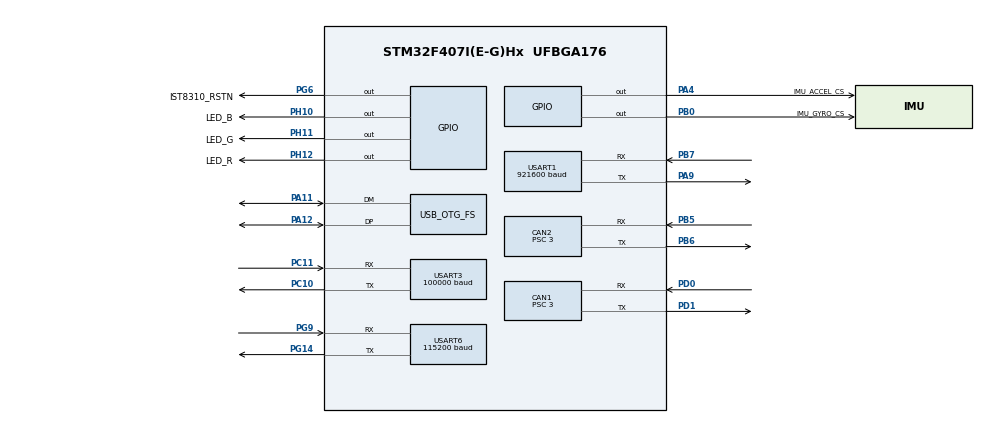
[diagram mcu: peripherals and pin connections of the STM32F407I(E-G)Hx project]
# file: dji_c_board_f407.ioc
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CAN1.BS1=CAN_BS1_10TQ
CAN1.BS2=CAN_BS2_3TQ
CAN1.CalculateBaudRate=1000000
CAN1.CalculateTimeBit=1000
CAN1.CalculateTimeQuantum=71.42857142857143
CAN1.Prescaler=3
CAN2.BS1=CAN_BS1_10TQ
CAN2.BS2=CAN_BS2_3TQ
CAN2.CalculateBaudRate=1000000
CAN2.CalculateTimeBit=1000
CAN2.CalculateTimeQuantum=71.42857142857143
CAN2.Prescaler=3
Dma.Request0=USART1_RX
Dma.Request1=USART1_TX
Dma.Request2=USART3_RX
Dma.Request3=USART6_RX
Dma.Request4=USART6_TX
Dma.USART1_RX.0.Direction=DMA_PERIPH_TO_MEMORY
Dma.USART1_RX.0.FIFOMode=DMA_FIFOMODE_DISABLE
Dma.USART1_RX.0.Instance=DMA2_Stream2
Dma.USART1_RX.0.MemDataAlignment=DMA_MDATAALIGN_BYTE
Dma.USART1_RX.0.MemInc=DMA_MINC_ENABLE
Dma.USART1_RX.0.Mode=DMA_NORMAL
Dma.USART1_RX.0.PeriphDataAlignment=DMA_PDATAALIGN_BYTE
Dma.USART1_RX.0.PeriphInc=DMA_PINC_DISABLE
Dma.USART1_RX.0.Priority=DMA_PRIORITY_LOW
Dma.USART1_TX.1.Direction=DMA_MEMORY_TO_PERIPH
Dma.USART1_TX.1.FIFOMode=DMA_FIFOMODE_DISABLE
Dma.USART1_TX.1.Instance=DMA2_Stream7
Dma.USART1_TX.1.MemDataAlignment=DMA_MDATAALIGN_BYTE
Dma.USART1_TX.1.MemInc=DMA_MINC_ENABLE
Dma.USART1_TX.1.Mode=DMA_NORMAL
Dma.USART1_TX.1.PeriphDataAlignment=DMA_PDATAALIGN_BYTE
Dma.USART1_TX.1.PeriphInc=DMA_PINC_DISABLE
Dma.USART1_TX.1.Priority=DMA_PRIORITY_LOW
Dma.USART3_RX.2.Direction=DMA_PERIPH_TO_MEMORY
Dma.USART3_RX.2.FIFOMode=DMA_FIFOMODE_DISABLE
Dma.USART3_RX.2.Instance=DMA1_Stream1
Dma.USART3_RX.2.MemDataAlignment=DMA_MDATAALIGN_BYTE
Dma.USART3_RX.2.MemInc=DMA_MINC_ENABLE
Dma.USART3_RX.2.Mode=DMA_CIRCULAR
Dma.USART3_RX.2.PeriphDataAlignment=DMA_PDATAALIGN_BYTE
Dma.USART3_RX.2.PeriphInc=DMA_PINC_DISABLE
Dma.USART3_RX.2.Priority=DMA_PRIORITY_VERY_HIGH
Dma.USART6_RX.3.Direction=DMA_PERIPH_TO_MEMORY
Dma.USART6_RX.3.FIFOMode=DMA_FIFOMODE_DISABLE
Dma.USART6_RX.3.Instance=DMA2_Stream1
Dma.USART6_RX.3.MemDataAlignment=DMA_MDATAALIGN_BYTE
Dma.USART6_RX.3.MemInc=DMA_MINC_ENABLE
Dma.USART6_RX.3.Mode=DMA_NORMAL
Dma.USART6_RX.3.PeriphDataAlignment=DMA_PDATAALIGN_BYTE
Dma.USART6_RX.3.PeriphInc=DMA_PINC_DISABLE
Dma.USART6_RX.3.Priority=DMA_PRIORITY_VERY_HIGH
Dma.USART6_TX.4.Direction=DMA_MEMORY_TO_PERIPH
Dma.USART6_TX.4.FIFOMode=DMA_FIFOMODE_DISABLE
Dma.USART6_TX.4.Instance=DMA2_Stream6
Dma.USART6_TX.4.MemDataAlignment=DMA_MDATAALIGN_BYTE
Dma.USART6_TX.4.MemInc=DMA_MINC_ENABLE
Dma.USART6_TX.4.Mode=DMA_NORMAL
Dma.USART6_TX.4.PeriphDataAlignment=DMA_PDATAALIGN_BYTE
Dma.USART6_TX.4.PeriphInc=DMA_PINC_DISABLE
Dma.USART6_TX.4.Priority=DMA_PRIORITY_VERY_HIGH
Mcu.Family=STM32F4
Mcu.Name=STM32F407I(E-G)Hx
Mcu.Package=UFBGA176
NVIC.CAN1_RX0_IRQn=true\:0\:0\:false\:false\:true\:false\:true\:true\:true
NVIC.CAN1_SCE_IRQn=true\:0\:0\:false\:false\:true\:false\:true\:true\:true
NVIC.CAN1_TX_IRQn=true\:0\:0\:false\:false\:true\:false\:true\:true\:true
NVIC.CAN2_RX0_IRQn=true\:0\:0\:true\:false\:true\:false\:true\:true\:true
NVIC.CAN2_SCE_IRQn=true\:0\:0\:true\:false\:true\:false\:true\:true\:true
NVIC.CAN2_TX_IRQn=true\:0\:0\:true\:false\:true\:false\:true\:true\:true
NVIC.DMA1_Stream1_IRQn=true\:0\:0\:false\:false\:true\:false\:false\:true\:true
NVIC.DMA2_Stream1_IRQn=true\:0\:0\:false\:false\:true\:false\:false\:true\:true
NVIC.DMA2_Stream2_IRQn=true\:0\:0\:false\:false\:true\:false\:false\:true\:true
NVIC.DMA2_Stream6_IRQn=true\:0\:0\:false\:false\:true\:false\:false\:true\:true
NVIC.DMA2_Stream7_IRQn=true\:0\:0\:false\:false\:true\:false\:false\:true\:true
NVIC.OTG_FS_IRQn=true\:5\:0\:false\:false\:true\:false\:true\:true\:true
NVIC.PriorityGroup=NVIC_PRIORITYGROUP_4
NVIC.TIM8_TRG_COM_TIM14_IRQn=true\:15\:0\:false\:false\:true\:false\:false\:true\:true
NVIC.TimeBase=TIM8_TRG_COM_TIM14_IRQn
NVIC.TimeBaseIP=TIM14
NVIC.USART1_IRQn=true\:0\:0\:false\:false\:true\:false\:true\:true\:true
NVIC.USART3_IRQn=true\:0\:0\:true\:false\:true\:false\:true\:true\:true
NVIC.USART6_IRQn=true\:0\:0\:false\:false\:true\:false\:true\:true\:true
PA13.Mode=Serial_Wire
PA13.Signal=SYS_JTMS-SWDIO
PA14.Mode=Serial_Wire
PA14.Signal=SYS_JTCK-SWCLK
PA4.GPIO_Label=IMU_ACCEL_CS
PA4.PinState=GPIO_PIN_SET
PA4.Signal=GPIO_Output
PA9.Mode=Asynchronous
PA9.Signal=USART1_TX
PA11.Mode=Device_Only
PA11.Signal=USB_OTG_FS_DM
PA12.Mode=Device_Only
PA12.Signal=USB_OTG_FS_DP
PB0.GPIO_Label=IMU_GYRO_CS
PB0.PinState=GPIO_PIN_SET
PB0.Signal=GPIO_Output
PB5.Mode=CAN_Activate
PB5.Signal=CAN2_RX
PB6.Mode=CAN_Activate
PB6.Signal=CAN2_TX
PB7.Mode=Asynchronous
PB7.Signal=USART1_RX
PC10.Mode=Asynchronous
PC10.Signal=USART3_TX
PC11.Mode=Asynchronous
PC11.Signal=USART3_RX
PD0.Mode=CAN_Activate
PD0.Signal=CAN1_RX
PD1.Mode=CAN_Activate
PD1.Signal=CAN1_TX
PG14.Mode=Asynchronous
PG14.Signal=USART6_TX
PG6.GPIO_Label=IST8310_RSTN
PG6.GPIO_Speed=GPIO_SPEED_FREQ_MEDIUM
PG6.PinState=GPIO_PIN_SET
PG6.Signal=GPIO_Output
PG9.Mode=Asynchronous
PG9.Signal=USART6_RX
PH0-OSC_IN.Mode=HSE-External-Oscillator
PH0-OSC_IN.Signal=RCC_OSC_IN
PH1-OSC_OUT.Mode=HSE-External-Oscillator
PH1-OSC_OUT.Signal=RCC_OSC_OUT
PH10.GPIO_Label=LED_B
PH10.PinState=GPIO_PIN_RESET
PH10.Signal=GPIO_Output
PH11.GPIO_Label=LED_G
PH11.PinState=GPIO_PIN_RESET
PH11.Signal=GPIO_Output
PH12.GPIO_Label=LED_R
PH12.PinState=GPIO_PIN_RESET
PH12.Signal=GPIO_Output
ProjectManager.HeapSize=0x4000
ProjectManager.StackSize=0x4500
ProjectManager.TargetToolchain=CMake
RCC.48MHZClocksFreq_Value=48000000
RCC.AHBFreq_Value=168000000
RCC.APB1CLKDivider=RCC_HCLK_DIV4
RCC.APB1Freq_Value=42000000
RCC.APB1TimFreq_Value=84000000
RCC.APB2CLKDivider=RCC_HCLK_DIV2
RCC.APB2Freq_Value=84000000
RCC.APB2TimFreq_Value=168000000
RCC.CortexFreq_Value=168000000
RCC.HCLKFreq_Value=168000000
RCC.HSE_VALUE=12000000
RCC.HSI_VALUE=16000000
RCC.LSE_VALUE=32768
RCC.PLLM=6
RCC.PLLN=168
RCC.PLLP=RCC_PLLP_DIV2
RCC.PLLQ=7
RCC.PLLSourceVirtual=RCC_PLLSOURCE_HSE
RCC.SYSCLKFreq_VALUE=168000000
RCC.SYSCLKSource=RCC_SYSCLKSOURCE_PLLCLK
RCC.VCOOutputFreq_Value=336000000
STMicroelectronics.X-CUBE-AZRTOS-F4.1.1.0.AZRTOS_APP_MEM_ALLOCATION_METHOD=1
STMicroelectronics.X-CUBE-AZRTOS-F4.1.1.0.TX_APP_MEM_POOL_SIZE=1024*11
STMicroelectronics.X-CUBE-AZRTOS-F4.1.1.0.TX_DISABLE_PREEMPTION_THRESHOLD=0
STMicroelectronics.X-CUBE-AZRTOS-F4.1.1.0.TX_DISABLE_REDUNDANT_CLEARING=0
STMicroelectronics.X-CUBE-AZRTOS-F4.1.1.0.TX_DISABLE_STACK_FILLING=0
STMicroelectronics.X-CUBE-AZRTOS-F4.1.1.0.TX_ENABLE_STACK_CHECKING=1
STMicroelectronics.X-CUBE-AZRTOS-F4.1.1.0.TX_INLINE_THREAD_RESUME_SUSPEND=0
STMicroelectronics.X-CUBE-AZRTOS-F4.1.1.0.TX_NOT_INTERRUPTABLE=0
STMicroelectronics.X-CUBE-AZRTOS-F4.1.1.0.TX_REACTIVATE_INLINE=0
STMicroelectronics.X-CUBE-AZRTOS-F4.1.1.0.TX_TIMER_PROCESS_IN_ISR=0
STMicroelectronics.X-CUBE-AZRTOS-F4.1.1.0.TX_TIMER_TICKS_PER_SECOND=1000
STMicroelectronics.X-CUBE-AZRTOS-F4.1.1.0.ThreadXCcRTOSJjThreadXJjCore=true
STMicroelectronics.X-CUBE-AZRTOS-F4.1.1.0.USBD_CDCACM_EPINCMD_ADDR=2
STMicroelectronics.X-CUBE-AZRTOS-F4.1.1.0.USBD_CDCACM_EPIN_ADDR=3
STMicroelectronics.X-CUBE-AZRTOS-F4.1.1.0.USBD_PRODUCT_STRING=PnX F407 CDC DEV
STMicroelectronics.X-CUBE-AZRTOS-F4.1.1.0.USBD_SERIAL_NUMBER=PNXF407DEV0001
STMicroelectronics.X-CUBE-AZRTOS-F4.1.1.0.USBXCcUSBJjUSBXJjCoreSystem=true
STMicroelectronics.X-CUBE-AZRTOS-F4.1.1.0.USBXCcUSBJjUSBXJjUXOoDeviceOoClassOoCDCOoACM=true
STMicroelectronics.X-CUBE-AZRTOS-F4.1.1.0.USBXCcUSBJjUSBXJjUXOoDeviceOoControllers=true
STMicroelectronics.X-CUBE-AZRTOS-F4.1.1.0.USBXCcUSBJjUSBXJjUXOoDeviceOoCoreStack=true
STMicroelectronics.X-CUBE-AZRTOS-F4.1.1.0.UX_DEVICE_APP_MEM_POOL_SIZE=1024*12
STMicroelectronics.X-CUBE-AZRTOS-F4.1.1.0.UX_SLAVE_REQUEST_DATA_MAX_LENGTH=512
STMicroelectronics.X-CUBE-AZRTOS-F4.1.1.0_IsAnAzureRtosMw=true
USART1.BaudRate=921600
USART1.VirtualMode=VM_ASYNC
USART3.BaudRate=100000
USART3.Mode=MODE_RX
USART3.Parity=PARITY_EVEN
USART3.VirtualMode=VM_ASYNC
USART3.WordLength=WORDLENGTH_9B
USART6.BaudRate=115200
USART6.VirtualMode=VM_ASYNC
USB_OTG_FS.VirtualMode=Device_Only
VP_STMicroelectronics.X-CUBE-AZRTOS-F4_VS_RTOSJjThreadX_6.1.10_1.1.0.Mode=RTOSJjThreadX
VP_STMicroelectronics.X-CUBE-AZRTOS-F4_VS_USBJjUSBX_6.1.10_1.1.0.Mode=USBJjUSBX
VP_SYS_VS_tim14.Mode=TIM14
board=custom

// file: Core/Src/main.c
/* USER CODE BEGIN Header */
/**
  ******************************************************************************
  * @file           : main.c
  * @brief          : Main program body
  ******************************************************************************
  * @attention
  *
  * Copyright (c) 2026 STMicroelectronics.
  * All rights reserved.
  *
  * This software is licensed under terms that can be found in the LICENSE file
  * in the root directory of this software component.
  * If no LICENSE file comes with this software, it is provided AS-IS.
  *
  ******************************************************************************
  */
/* USER CODE END Header */
#ifndef PNX_F407_CAN_ENABLED
#error "PNX_F407_CAN_ENABLED must be derived from the image source graph"
#endif
#ifndef PNX_F407_USART_ENABLED
#error "PNX_F407_USART_ENABLED must be derived from the image source graph"
#endif

#include "app_threadx.h"
#include "main.h"
#if PNX_F407_CAN_ENABLED
#include "can.h"
#endif
#include "dma.h"
#if PNX_F407_USART_ENABLED
#include "usart.h"
#endif
#if PNX_F407_USB_ENABLED
#include "usb_otg.h"
#endif
#include "gpio.h"

/* USER CODE BEGIN Includes */
#include "bsp_diagnostics.h"
/* USER CODE END Includes */

void SystemClock_Config(void);

int main(void)
{

  /* USER CODE BEGIN 1 */
  bsp_diagnostics_boot();
  /* USER CODE END 1 */

  /* MCU Configuration--------------------------------------------------------*/

  /* Reset of all peripherals, Initializes the Flash interface and the Systick. */
  HAL_Init();

  /* Configure the system clock */
  SystemClock_Config();

  /* Initialize all configured peripherals */
  MX_GPIO_Init();
  MX_DMA_Init();
#if PNX_F407_CAN_ENABLED
  MX_CAN1_Init();
  MX_CAN2_Init();
#endif
#if PNX_F407_USART_ENABLED
  MX_USART3_UART_Init();
  MX_USART6_UART_Init();
  MX_USART1_UART_Init();
#endif
#if PNX_F407_USB_ENABLED
  MX_USB_OTG_FS_PCD_Init();
#endif

  MX_ThreadX_Init();

  /* We should never get here as control is now taken by the scheduler */

  /* Infinite loop */
  while (1)
  {

  }
}

void SystemClock_Config(void)
{
  RCC_OscInitTypeDef RCC_OscInitStruct = {0};
  RCC_ClkInitTypeDef RCC_ClkInitStruct = {0};

  /** Configure the main internal regulator output voltage
  */
  __HAL_RCC_PWR_CLK_ENABLE();
  __HAL_PWR_VOLTAGESCALING_CONFIG(PWR_REGULATOR_VOLTAGE_SCALE1);

  /** Initializes the RCC Oscillators according to the specified parameters
  * in the RCC_OscInitTypeDef structure.
  */
  RCC_OscInitStruct.OscillatorType = RCC_OSCILLATORTYPE_HSE;
  RCC_OscInitStruct.HSEState = RCC_HSE_ON;
  RCC_OscInitStruct.PLL.PLLState = RCC_PLL_ON;
  RCC_OscInitStruct.PLL.PLLSource = RCC_PLLSOURCE_HSE;
  RCC_OscInitStruct.PLL.PLLM = 6;
  RCC_OscInitStruct.PLL.PLLN = 168;
  RCC_OscInitStruct.PLL.PLLP = RCC_PLLP_DIV2;
  RCC_OscInitStruct.PLL.PLLQ = 7;
  if (HAL_RCC_OscConfig(&RCC_OscInitStruct) != HAL_OK)
  {
    Error_Handler();
  }

  /** Initializes the CPU, AHB and APB buses clocks
  */
  RCC_ClkInitStruct.ClockType = RCC_CLOCKTYPE_HCLK|RCC_CLOCKTYPE_SYSCLK
                              |RCC_CLOCKTYPE_PCLK1|RCC_CLOCKTYPE_PCLK2;
  RCC_ClkInitStruct.SYSCLKSource = RCC_SYSCLKSOURCE_PLLCLK;
  RCC_ClkInitStruct.AHBCLKDivider = RCC_SYSCLK_DIV1;
#if PNX_F407_PS2_RECEIVER_SAFE_PCLK1
  RCC_ClkInitStruct.APB1CLKDivider = RCC_HCLK_DIV8;
#else
  RCC_ClkInitStruct.APB1CLKDivider = RCC_HCLK_DIV4;
#endif
  RCC_ClkInitStruct.APB2CLKDivider = RCC_HCLK_DIV2;

  if (HAL_RCC_ClockConfig(&RCC_ClkInitStruct, FLASH_LATENCY_5) != HAL_OK)
  {
    Error_Handler();
  }
}

/* USER CODE BEGIN 4 */
void Error_Handler(void) __attribute__((noinline, noreturn));

/* USER CODE END 4 */

void HAL_TIM_PeriodElapsedCallback(TIM_HandleTypeDef *htim)
{
  if (htim->Instance == TIM14)
  {
    HAL_IncTick();
  }
}

void Error_Handler(void)
{
  /* USER CODE BEGIN Error_Handler_Debug */
  bsp_diagnostics_capture_error_handler(
    (uint32_t)(uintptr_t)__builtin_return_address(0));
  /* USER CODE END Error_Handler_Debug */
}
